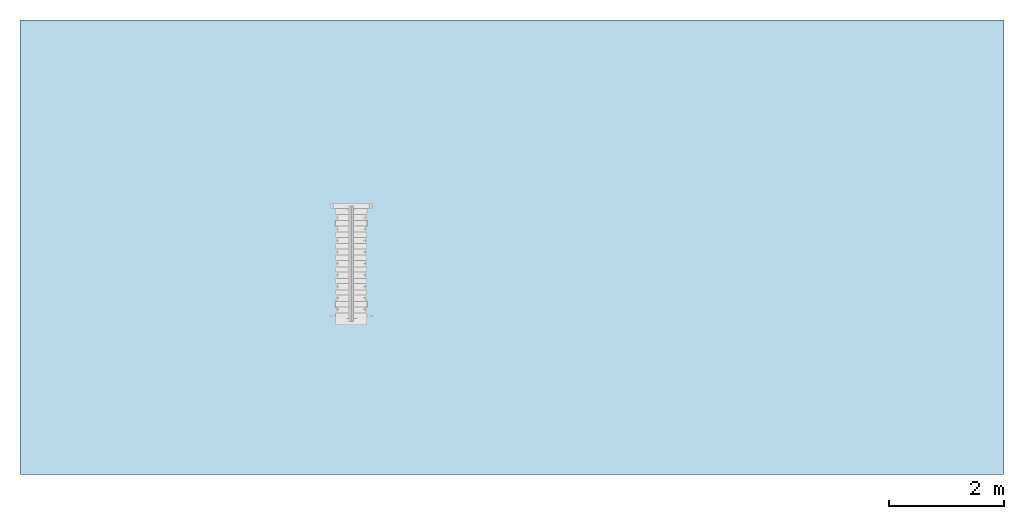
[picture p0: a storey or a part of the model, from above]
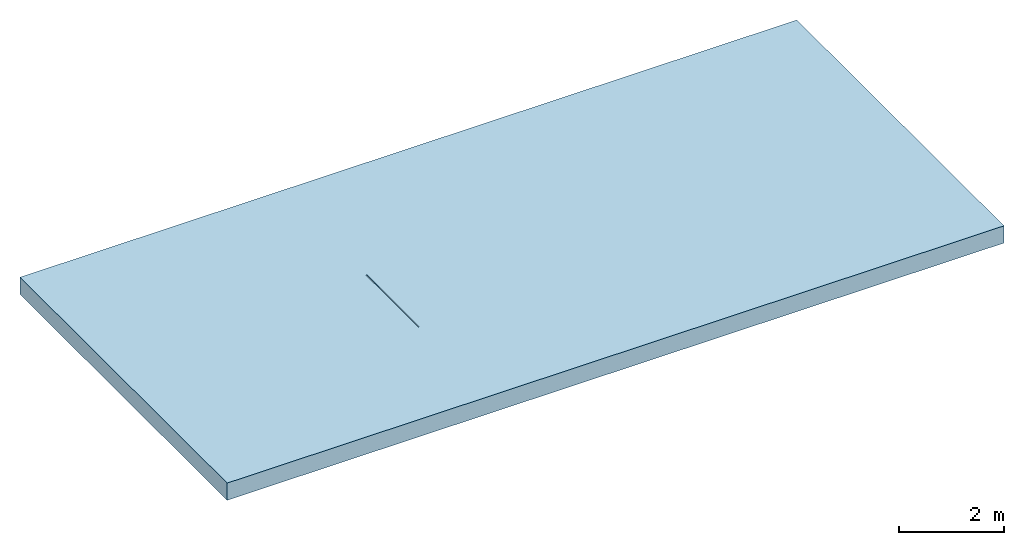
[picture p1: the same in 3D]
Properties of the parts of a building model (IFC2X3)

# File
Description: ViewDefinition [CoordinationView]
File name: 32834 - Q-Slot Edge - G.S.ifc
Time: 2013-07-11T17:00:21
Written by: Autodesk Revit 2013
Made in: 20120221_2030(x64)

# IfcProject, Project Number
LongName: Project Name; Phase: Project Status

# IfcSite, Default
RefLatitude: 42, 21, 30, 344238; RefLongitude: -71, -3, -35, -194702; RefElevation: 0 mm

# IfcBuilding
Pset_BuildingCommon - NumberOfStoreys: 1
Other - Project Name: Project Name; Project Number: Project Number; Project Status: Project Status; Project Issue Date: Issue Date; Project Address: ## Street City, State Zip; Client Name: Owner

# IfcBuildingStorey, Level 1
LongName: Level 1; Elevation: 0 mm
Constraints - Elevation Base: 0; Elevation: 0 mm
Graphics - Line Weight: 1; Line Pattern: Center; Symbol: M_Level Head - Circle: M_Level Head - Circle; Symbol at End 1 Default: no; Color: 0; Symbol at End 2 Default: yes
Identity Data - Name: Level 1; Structural: no; Building Story: yes
Dimensions - Computation Height: 0 mm

# IfcFlowTerminal: 32834 - Q-Slot Edge - G.S, Qmax 700:32834 - Q-Slot Edge - G.S:32834 - Q-Slot Edge - G.S:502881
In: Level 1
Construction - 32854_Chamber connector (at Female end): no; 32835_Closing End cap (at Female end): no; 32882_550-700 Step Connector: no; 32835_Closing End cap (at Male end): yes; 32854_Chamber connector (at Male end): no; V_CoarseE1: no; V_Coarse_E5: yes; E3-QFlow-GalvSteel: no; E1-QFlow-DuctileIron: no; E4-QGuard-GalvSteel: no; E2-QGuard-DuctileIron: no; E5-QSlot-GalvSteel: yes
Identity Data - Mark: 37; Price: POA - contact ACO; Product Page URL: http://www.aco.co.uk/product_detail.php?id=79; Assembly Code: D2040; Model Description: High capacity slot drainage channel system; Cost: 0; Manufacturer: ACO Technologies plc - ACO Water Management Division; OmniClass Number: 23.70.50.24; Maintenance Guidelines: http://www.aco.co.uk/download.php?id=220; Address: ACO Business Park, Hitchin Road, Shefford, Bedfordshire, United Kingdom SG17 5TE; e-mail Sales: customersupport@aco.co.uk; URL: www.aco.co.uk; Product Code: 32834; OmniClass Title: Rainwater Removal; Model: ACO Qmax 700; Fax: +44 (0)1462 815895; Telephone: +44 (0)1462 816666; Product Brochure: http://www.aco.co.uk/download.php?id=220; Assembly Description: Rain Water Drainage; e-mail Technical: technical@aco.co.uk; Type Comments: ACO Qmax 700 channel assembly complete with ACO Q-Slot galvanised steel edge rail; Installation Guidelines: http://www.aco.co.uk/download.php?id=220
Phasing - Phase Created: New Construction
Constraints - Level: Level: Level 1; Moves With Nearby Elements: no
Data - Hydraulic Performance: http://www.aco.co.uk/download.php?id=220; Product Standard: BS EN 1433:2002 CE marked; ACO Hydraulic Design Software: http://www.acodesign.co.uk; Invert Depth: 1050mm; Product Dimensions: 2000mm x 730mm x 1170mm (LxWxH); Product Weight: 47 kg; Load Class: A 15 - F 900; Drainage Slot Width: 10mm; Drainage Slot Intake Area: 10000mm²/m; Concrete Surround Volume - Load Class A 15 - D 400: 0.56 m³/m; Installation - Concrete Grade: Refer to brochure; Installation - Reinforcement Details: Refer to brochure; Concrete Surround Volume - Load Class E 600 - F 900: 0.72 m³/m; Channel C.S.A: 249703mm²
Green Building Properties - Edge Rail Recycled Material Content: Between 40% - 90%; Seal Recyclable: Fully recyclable; Seal Recycled Material Content: 0%; Channel Recycled Material Content: Variable %; Channel Recyclable: Fully recyclable; Edge Rail Recyclable: Fully recyclable
General - TagNumber: 0; SerialNumber: 0
Materials and Finishes - Edge Rail Colour: Silver; Channel Colour: Black; Seal Material: EPDM; Edge Rail Material: Steel; Seal Colour: Black; Channel Material: Medium Density Polyethylene; Edge Rail Finish: Galvanised
Other - Created by: www.aco.co.uk; Revision: 1
Dimensions - StepConn-Origin: 680.3 mm; ChamberOrigin: 580 mm; Width Overall: 730 mm; ClosingEndCapOrigin: 670.2 mm; Length: 2000 mm; Depth Overall: 1170 mm; Floor Opening Width: 18 mm
Model Properties - Closing End Cap Model Description: High capacity slot drainage channel system; 550-700 Step Connector Recyclable: Fully recyclable; Closing End Cap Product Code: 32835; 550-700 Step Connector Dimensions: 730mm x 45mm x 865mm (LxWxH); 550-700 Step Connector Recycled Material Content: 0%; Closing End Cap Recyclable: Fully recyclable; 550-700 Step Connector Product Code: 32882; Chamber Connector Weight: 15.8 kg; Closing End Cap Material: High Density Polyethylene; 550-700 Step Connector Colour: Black; Closing End Cap Colour: Black; Chamber Connector Recyclable: Fully recyclable; 550-700 Step Connector Material: High Density Polyethylene; Chamber Connector Channel Colour: Black; 550-700 Step Connector Weight: 2.5 kg; Chamber Connector Recycled Material Content: Variable %; Closing End Cap Dimensions: 730mm x 12mm x 865mm (LxWxH); Chamber Connector Model Description: High capacity slot drainage channel system; Closing End Cap Recycled Material Content: 0%; 550-700 Step Connector Model Description: High capacity slot drainage channel system; Chamber Connector Product Code: 32854; Closing End Cap Weight: 4.9 kg; Chamber Connector Dimensions: Female End=800mm x 715mm x 895mm, Male End=800mm x 715mm x 845mm (LxWxH); Chamber Connector Channel Material: Medium Density Polyethylene

# IfcOpeningElement: Opening
In: Level 1
Dimensions - Volume: 53517600000 mm3; Area: 135054000 mm2; Perimeter: 50000 mm; Thickness: 400 mm
Constraints - Level: Level: Level 1; Related to Mass: no; Height Offset From Level: 0 mm; Room Bounding: yes
Structural - Structural: no; Enable Analytical Model: no
Phasing - Phase Created: New Construction
Analytical Properties - Roughness: 1; Absorptance: 0.1
Construction - Default Thickness: 400 mm; Function: 0
Graphics - Coarse Scale Fill Color: 0
Materials and Finishes - Structural Material: Plant

# IfcSlab: Floor:Generic Floor - 400mm, Floor:Generic Floor - 400mm:193825
In: Level 1
PredefinedType: FLOOR; Material: Plant 400 mm
Dimensions - Volume: 53517600000 mm3; Area: 135054000 mm2; Perimeter: 50000 mm; Thickness: 400 mm
Constraints - Level: Level: Level 1; Related to Mass: no; Height Offset From Level: 0 mm; Room Bounding: yes
Structural - Structural: no; Enable Analytical Model: no
Phasing - Phase Created: New Construction
Pset_SlabCommon - Reference: Generic Floor - 400mm; IsExternal: no; LoadBearing: yes
Analytical Properties - Roughness: 1; Absorptance: 0.1
Construction - Default Thickness: 400 mm; Function: 0
Graphics - Coarse Scale Fill Color: 0
Materials and Finishes - Structural Material: Plant
